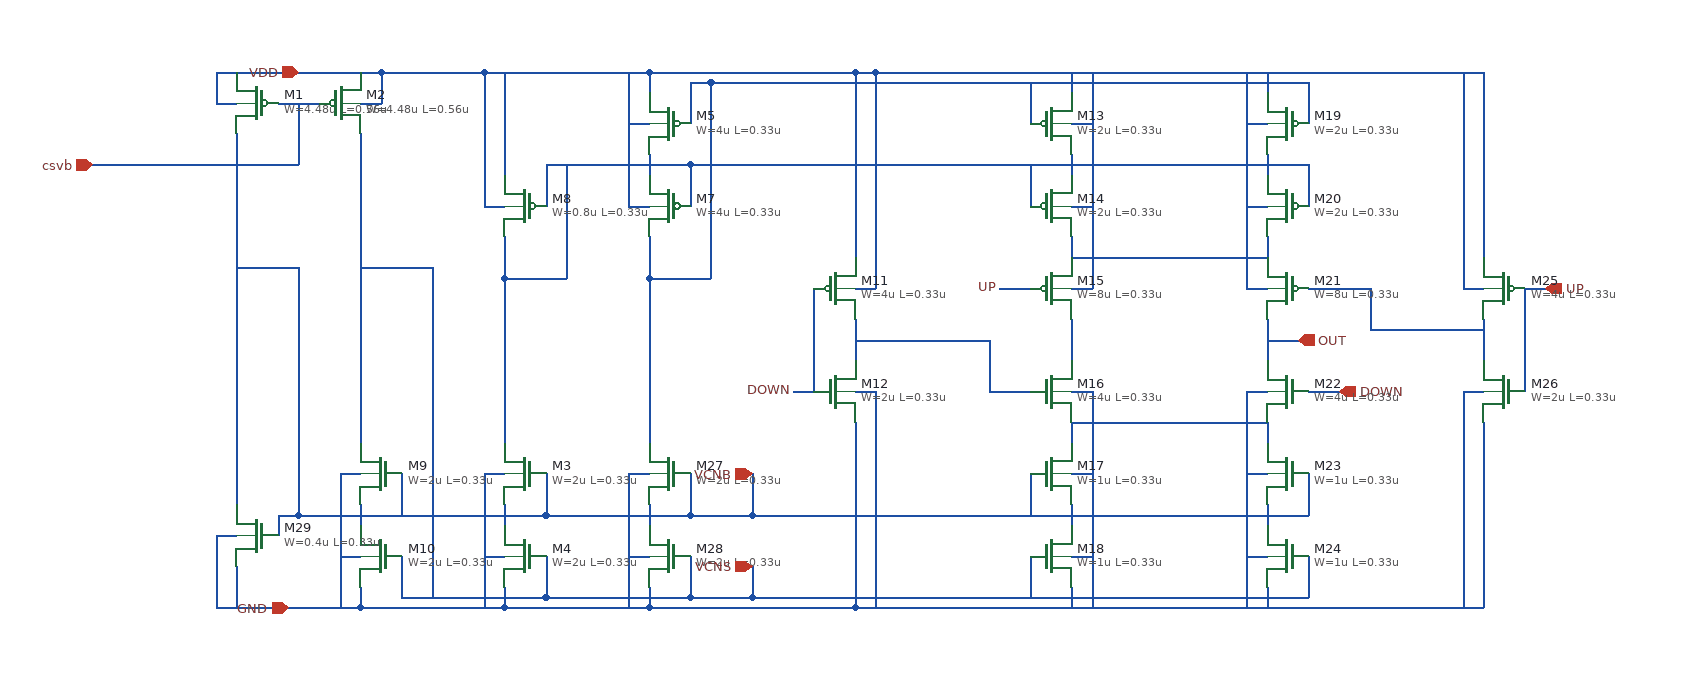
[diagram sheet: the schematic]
v {xschem version=3.4.5 file_version=1.2
}
G {}
K {}
V {}
S {}
E {}
N 900 -360 900 -320 {
lab=OUT}
N 940 -290 970 -290 {
lab=DOWN}
N 1110 -360 1110 -320 {
lab=#net1}
N 940 -390 980 -390 {
lab=#net1}
N 1150 -390 1150 -290 {
lab=UP}
N 1150 -390 1170 -390 {
lab=UP}
N 1090 -390 1110 -390 {
lab=VDD}
N 1090 -290 1110 -290 {
lab=GND}
N 880 -390 900 -390 {
lab=VDD}
N 880 -290 900 -290 {
lab=GND}
N 710 -360 710 -320 {
lab=#net2}
N 640 -390 670 -390 {
lab=UP}
N 500 -360 500 -320 {
lab=#net3}
N 630 -290 670 -290 {
lab=#net3}
N 630 -340 630 -290 {
lab=#net3}
N 500 -340 630 -340 {
lab=#net3}
N 460 -390 460 -290 {
lab=DOWN}
N 440 -290 460 -290 {
lab=DOWN}
N 500 -390 520 -390 {
lab=VDD}
N 500 -290 520 -290 {
lab=GND}
N 710 -390 730 -390 {
lab=VDD}
N 710 -290 730 -290 {
lab=GND}
N 710 -420 900 -420 {
lab=#net4}
N 710 -260 900 -260 {
lab=#net5}
N 900 -340 930 -340 {
lab=OUT}
N 980 -390 1000 -390 {
lab=#net1}
N 1000 -350 1110 -350 {
lab=#net1}
N 1000 -390 1000 -350 {
lab=#net1}
N 710 -210 730 -210 {
lab=GND}
N 710 -130 730 -130 {
lab=GND}
N 900 -600 900 -580 {
lab=VDD}
N 880 -550 900 -550 {
lab=VDD}
N 880 -470 900 -470 {
lab=VDD}
N 900 -520 900 -500 {
lab=#net6}
N 940 -510 940 -470 {
lab=#net7}
N 940 -590 940 -550 {
lab=#net8}
N 400 -590 760 -590 {
lab=#net8}
N 400 -510 760 -510 {
lab=#net7}
N 710 -180 710 -160 {
lab=#net9}
N 710 -100 710 -80 {
lab=GND}
N 670 -210 670 -170 {
lab=VCNB}
N 670 -130 670 -90 {
lab=GND}
N 900 -440 900 -420 {
lab=#net4}
N 500 -600 500 -420 {
lab=VDD}
N 520 -600 520 -390 {
lab=VDD}
N 730 -600 730 -390 {
lab=VDD}
N 880 -600 880 -390 {
lab=VDD}
N 1110 -600 1110 -420 {
lab=VDD}
N 1090 -600 1090 -390 {
lab=VDD}
N 500 -260 500 -80 {
lab=GND}
N 520 -290 520 -80 {
lab=GND}
N 880 -290 880 -80 {
lab=GND}
N 710 -260 710 -240 {
lab=#net5}
N 1090 -290 1090 -80 {
lab=GND}
N 1110 -260 1110 -80 {
lab=GND}
N 500 -80 1110 -80 {
lab=GND}
N 710 -600 710 -580 {
lab=VDD}
N 710 -550 730 -550 {
lab=VDD}
N 710 -470 730 -470 {
lab=VDD}
N 710 -520 710 -500 {
lab=#net10}
N 670 -510 670 -470 {
lab=#net7}
N 670 -590 670 -550 {
lab=#net8}
N 710 -440 710 -420 {
lab=#net4}
N 730 -290 730 -80 {
lab=GND}
N 880 -210 900 -210 {
lab=GND}
N 880 -130 900 -130 {
lab=GND}
N 900 -180 900 -160 {
lab=#net11}
N 900 -100 900 -80 {
lab=GND}
N 940 -210 940 -170 {
lab=VCNB}
N 940 -130 940 -90 {
lab=GND}
N 900 -260 900 -240 {
lab=#net5}
N 760 -90 940 -90 {
lab=GND}
N 760 -170 940 -170 {
lab=VCNB}
N 760 -590 940 -590 {
lab=#net8}
N 760 -510 940 -510 {
lab=#net7}
N 520 -600 1110 -600 {
lab=VDD}
N 500 -600 520 -600 {
lab=VDD}
N 400 -170 760 -170 {
lab=VCNB}
N 400 -90 760 -90 {
lab=GND}
N -120 -570 -100 -570 {
lab=VDD}
N -120 -600 -120 -570 {
lab=VDD}
N -60 -570 -20 -570 {
lab=csvb}
N -120 -600 -100 -600 {
lab=VDD}
N 20 -570 40 -570 {
lab=VDD}
N 40 -600 40 -570 {
lab=VDD}
N 20 -600 40 -600 {
lab=VDD}
N -100 -600 20 -600 {
lab=VDD}
N 0 -210 20 -210 {
lab=GND}
N 0 -210 0 -80 {
lab=GND}
N 0 -130 20 -130 {
lab=GND}
N 20 -180 20 -160 {
lab=#net12}
N 20 -100 20 -80 {
lab=GND}
N -120 -80 -20 -80 {
lab=GND}
N -60 -170 -40 -170 {
lab=VCNB}
N -100 -410 -40 -410 {
lab=VCNB}
N 60 -210 60 -170 {
lab=VCNB}
N 60 -130 60 -90 {
lab=GND}
N 60 -90 80 -90 {
lab=GND}
N -40 -170 100 -170 {
lab=VCNB}
N -40 -280 -40 -170 {
lab=VCNB}
N -100 -450 -100 -370 {
lab=VCNB}
N -20 -80 20 -80 {
lab=GND}
N 20 -450 20 -370 {
lab=GND}
N 140 -210 160 -210 {
lab=GND}
N 140 -130 160 -130 {
lab=GND}
N 160 -180 160 -160 {
lab=#net13}
N 160 -100 160 -80 {
lab=GND}
N 200 -210 200 -170 {
lab=VCNB}
N 200 -130 200 -90 {
lab=GND}
N 100 -170 200 -170 {
lab=VCNB}
N 80 -90 200 -90 {
lab=GND}
N 20 -80 160 -80 {
lab=GND}
N 140 -210 140 -80 {
lab=GND}
N 300 -600 300 -580 {
lab=VDD}
N 280 -550 300 -550 {
lab=VDD}
N 280 -470 300 -470 {
lab=VDD}
N 280 -600 280 -470 {
lab=VDD}
N 300 -520 300 -500 {
lab=#net14}
N 340 -510 340 -470 {
lab=#net7}
N 340 -590 340 -550 {
lab=#net8}
N 300 -400 360 -400 {
lab=#net8}
N 160 -600 160 -500 {
lab=VDD}
N 140 -470 160 -470 {
lab=VDD}
N 140 -600 140 -470 {
lab=VDD}
N 200 -510 340 -510 {
lab=#net7}
N 200 -510 200 -470 {
lab=#net7}
N 160 -400 220 -400 {
lab=#net7}
N 140 -600 240 -600 {
lab=VDD}
N 160 -440 160 -400 {
lab=#net7}
N 300 -440 300 -400 {
lab=#net8}
N 220 -510 220 -400 {
lab=#net7}
N 340 -590 360 -590 {
lab=#net8}
N 360 -590 360 -400 {
lab=#net8}
N 240 -600 300 -600 {
lab=VDD}
N 160 -400 160 -370 {
lab=#net7}
N 280 -210 300 -210 {
lab=GND}
N 280 -130 300 -130 {
lab=GND}
N 300 -180 300 -160 {
lab=#net15}
N 300 -100 300 -80 {
lab=GND}
N 340 -210 340 -170 {
lab=VCNB}
N 340 -130 340 -90 {
lab=GND}
N 240 -170 340 -170 {
lab=VCNB}
N 280 -210 280 -80 {
lab=GND}
N 160 -80 300 -80 {
lab=GND}
N 200 -170 240 -170 {
lab=VCNB}
N 200 -90 340 -90 {
lab=GND}
N 300 -400 300 -370 {
lab=#net8}
N 340 -510 400 -510 {
lab=#net7}
N 360 -590 400 -590 {
lab=#net8}
N 20 -540 20 -450 {
lab=GND}
N -100 -540 -100 -450 {
lab=VCNB}
N -240 -510 -40 -510 {
lab=csvb}
N 40 -600 140 -600 {
lab=VDD}
N 90 -270 90 -90 {
lab=GND}
N 20 -410 90 -410 {
lab=GND}
N 90 -410 90 -400 {
lab=GND}
N -40 -570 -40 -510 {
lab=csvb}
N -120 -150 -100 -150 {
lab=GND}
N -100 -120 -100 -80 {
lab=GND}
N -60 -170 -60 -150 {
lab=VCNB}
N 340 -90 400 -90 {
lab=GND}
N 340 -170 400 -170 {
lab=VCNB}
N 310 -80 500 -80 {
lab=GND}
N 300 -80 310 -80 {
lab=GND}
N 300 -600 500 -600 {
lab=VDD}
N 300 -370 300 -240 {
lab=#net8}
N 160 -370 160 -240 {
lab=#net7}
N 90 -400 90 -270 {
lab=GND}
N 20 -370 20 -240 {
lab=GND}
N -100 -370 -100 -240 {
lab=VCNB}
N -40 -410 -40 -280 {
lab=VCNB}
N 400 -120 400 -90 {
lab=GND}
N 400 -210 400 -170 {
lab=VCNB}
N -120 -150 -120 -80 {
lab=GND}
N -100 -240 -100 -180 {
lab=VCNB}
C {devices/ipin.sym} 970 -290 0 1 {name=p7 lab=DOWN}
C {devices/ipin.sym} 1170 -390 0 1 {name=p6 lab=UP}
C {symbols/pfet_03v3.sym} 690 -390 0 0 {name=M15
L=0.33u
W=8u
nf=1
mult=1
ad="'int((nf+1)/2) * W/nf * 0.18u'"
pd="'2*int((nf+1)/2) * (W/nf + 0.18u)'"
as="'int((nf+2)/2) * W/nf * 0.18u'"
ps="'2*int((nf+2)/2) * (W/nf + 0.18u)'"
nrd="'0.18u / W'" nrs="'0.18u / W'"
sa=0 sb=0 sd=0
model=pfet_03v3
spiceprefix=X
}
C {symbols/nfet_03v3.sym} 690 -290 0 0 {name=M16
L=0.33u
W=4u
nf=1
mult=1
ad="'int((nf+1)/2) * W/nf * 0.18u'"
pd="'2*int((nf+1)/2) * (W/nf + 0.18u)'"
as="'int((nf+2)/2) * W/nf * 0.18u'"
ps="'2*int((nf+2)/2) * (W/nf + 0.18u)'"
nrd="'0.18u / W'" nrs="'0.18u / W'"
sa=0 sb=0 sd=0
model=nfet_03v3
spiceprefix=X
}
C {symbols/pfet_03v3.sym} 480 -390 0 0 {name=M11
L=0.33u
W=4u
nf=1
mult=1
ad="'int((nf+1)/2) * W/nf * 0.18u'"
pd="'2*int((nf+1)/2) * (W/nf + 0.18u)'"
as="'int((nf+2)/2) * W/nf * 0.18u'"
ps="'2*int((nf+2)/2) * (W/nf + 0.18u)'"
nrd="'0.18u / W'" nrs="'0.18u / W'"
sa=0 sb=0 sd=0
model=pfet_03v3
spiceprefix=X
}
C {symbols/nfet_03v3.sym} 480 -290 0 0 {name=M12
L=0.33u
W=2u
nf=1
mult=1
ad="'int((nf+1)/2) * W/nf * 0.18u'"
pd="'2*int((nf+1)/2) * (W/nf + 0.18u)'"
as="'int((nf+2)/2) * W/nf * 0.18u'"
ps="'2*int((nf+2)/2) * (W/nf + 0.18u)'"
nrd="'0.18u / W'" nrs="'0.18u / W'"
sa=0 sb=0 sd=0
model=nfet_03v3
spiceprefix=X
}
C {devices/lab_wire.sym} 440 -290 0 0 {name=p3 sig_type=std_logic lab=DOWN}
C {devices/lab_wire.sym} 640 -390 0 0 {name=p4 sig_type=std_logic lab=UP}
C {symbols/nfet_03v3.sym} 690 -210 0 0 {name=M17
L=0.33u
W=1u
nf=1
mult=1
ad="'int((nf+1)/2) * W/nf * 0.18u'"
pd="'2*int((nf+1)/2) * (W/nf + 0.18u)'"
as="'int((nf+2)/2) * W/nf * 0.18u'"
ps="'2*int((nf+2)/2) * (W/nf + 0.18u)'"
nrd="'0.18u / W'" nrs="'0.18u / W'"
sa=0 sb=0 sd=0
model=nfet_03v3
spiceprefix=X
}
C {devices/opin.sym} 930 -340 0 0 {name=p5 lab=OUT}
C {symbols/nfet_03v3.sym} 690 -130 0 0 {name=M18
L=0.33u
W=1u
nf=1
mult=1
ad="'int((nf+1)/2) * W/nf * 0.18u'"
pd="'2*int((nf+1)/2) * (W/nf + 0.18u)'"
as="'int((nf+2)/2) * W/nf * 0.18u'"
ps="'2*int((nf+2)/2) * (W/nf + 0.18u)'"
nrd="'0.18u / W'" nrs="'0.18u / W'"
sa=0 sb=0 sd=0
model=nfet_03v3
spiceprefix=X
}
C {symbols/pfet_03v3.sym} 690 -550 0 0 {name=M13
L=0.33u
W=2u
nf=1
mult=1
ad="'int((nf+1)/2) * W/nf * 0.18u'"
pd="'2*int((nf+1)/2) * (W/nf + 0.18u)'"
as="'int((nf+2)/2) * W/nf * 0.18u'"
ps="'2*int((nf+2)/2) * (W/nf + 0.18u)'"
nrd="'0.18u / W'" nrs="'0.18u / W'"
sa=0 sb=0 sd=0
model=pfet_03v3
spiceprefix=X
}
C {symbols/pfet_03v3.sym} 690 -470 0 0 {name=M14
L=0.33u
W=2u
nf=1
mult=1
ad="'int((nf+1)/2) * W/nf * 0.18u'"
pd="'2*int((nf+1)/2) * (W/nf + 0.18u)'"
as="'int((nf+2)/2) * W/nf * 0.18u'"
ps="'2*int((nf+2)/2) * (W/nf + 0.18u)'"
nrd="'0.18u / W'" nrs="'0.18u / W'"
sa=0 sb=0 sd=0
model=pfet_03v3
spiceprefix=X
}
C {symbols/pfet_03v3.sym} 920 -550 0 1 {name=M19
L=0.33u
W=2u
nf=1
mult=1
ad="'int((nf+1)/2) * W/nf * 0.18u'"
pd="'2*int((nf+1)/2) * (W/nf + 0.18u)'"
as="'int((nf+2)/2) * W/nf * 0.18u'"
ps="'2*int((nf+2)/2) * (W/nf + 0.18u)'"
nrd="'0.18u / W'" nrs="'0.18u / W'"
sa=0 sb=0 sd=0
model=pfet_03v3
spiceprefix=X
}
C {symbols/pfet_03v3.sym} 920 -470 0 1 {name=M20
L=0.33u
W=2u
nf=1
mult=1
ad="'int((nf+1)/2) * W/nf * 0.18u'"
pd="'2*int((nf+1)/2) * (W/nf + 0.18u)'"
as="'int((nf+2)/2) * W/nf * 0.18u'"
ps="'2*int((nf+2)/2) * (W/nf + 0.18u)'"
nrd="'0.18u / W'" nrs="'0.18u / W'"
sa=0 sb=0 sd=0
model=pfet_03v3
spiceprefix=X
}
C {symbols/pfet_03v3.sym} 920 -390 0 1 {name=M21
L=0.33u
W=8u
nf=1
mult=1
ad="'int((nf+1)/2) * W/nf * 0.18u'"
pd="'2*int((nf+1)/2) * (W/nf + 0.18u)'"
as="'int((nf+2)/2) * W/nf * 0.18u'"
ps="'2*int((nf+2)/2) * (W/nf + 0.18u)'"
nrd="'0.18u / W'" nrs="'0.18u / W'"
sa=0 sb=0 sd=0
model=pfet_03v3
spiceprefix=X
}
C {symbols/nfet_03v3.sym} 920 -290 0 1 {name=M22
L=0.33u
W=4u
nf=1
mult=1
ad="'int((nf+1)/2) * W/nf * 0.18u'"
pd="'2*int((nf+1)/2) * (W/nf + 0.18u)'"
as="'int((nf+2)/2) * W/nf * 0.18u'"
ps="'2*int((nf+2)/2) * (W/nf + 0.18u)'"
nrd="'0.18u / W'" nrs="'0.18u / W'"
sa=0 sb=0 sd=0
model=nfet_03v3
spiceprefix=X
}
C {symbols/nfet_03v3.sym} 920 -210 0 1 {name=M23
L=0.33u
W=1u
nf=1
mult=1
ad="'int((nf+1)/2) * W/nf * 0.18u'"
pd="'2*int((nf+1)/2) * (W/nf + 0.18u)'"
as="'int((nf+2)/2) * W/nf * 0.18u'"
ps="'2*int((nf+2)/2) * (W/nf + 0.18u)'"
nrd="'0.18u / W'" nrs="'0.18u / W'"
sa=0 sb=0 sd=0
model=nfet_03v3
spiceprefix=X
}
C {symbols/nfet_03v3.sym} 920 -130 0 1 {name=M24
L=0.33u
W=1u
nf=1
mult=1
ad="'int((nf+1)/2) * W/nf * 0.18u'"
pd="'2*int((nf+1)/2) * (W/nf + 0.18u)'"
as="'int((nf+2)/2) * W/nf * 0.18u'"
ps="'2*int((nf+2)/2) * (W/nf + 0.18u)'"
nrd="'0.18u / W'" nrs="'0.18u / W'"
sa=0 sb=0 sd=0
model=nfet_03v3
spiceprefix=X
}
C {symbols/pfet_03v3.sym} 1130 -390 0 1 {name=M25
L=0.33u
W=4u
nf=1
mult=1
ad="'int((nf+1)/2) * W/nf * 0.18u'"
pd="'2*int((nf+1)/2) * (W/nf + 0.18u)'"
as="'int((nf+2)/2) * W/nf * 0.18u'"
ps="'2*int((nf+2)/2) * (W/nf + 0.18u)'"
nrd="'0.18u / W'" nrs="'0.18u / W'"
sa=0 sb=0 sd=0
model=pfet_03v3
spiceprefix=X
}
C {symbols/nfet_03v3.sym} 1130 -290 0 1 {name=M26
L=0.33u
W=2u
nf=1
mult=1
ad="'int((nf+1)/2) * W/nf * 0.18u'"
pd="'2*int((nf+1)/2) * (W/nf + 0.18u)'"
as="'int((nf+2)/2) * W/nf * 0.18u'"
ps="'2*int((nf+2)/2) * (W/nf + 0.18u)'"
nrd="'0.18u / W'" nrs="'0.18u / W'"
sa=0 sb=0 sd=0
model=nfet_03v3
spiceprefix=X
}
C {symbols/pfet_03v3.sym} -80 -570 0 1 {name=M1
L=0.56u
W=4.48u
nf=1
m=1
ad="'int((nf+1)/2) * W/nf * 0.18u'"
pd="'2*int((nf+1)/2) * (W/nf + 0.18u)'"
as="'int((nf+2)/2) * W/nf * 0.18u'"
ps="'2*int((nf+2)/2) * (W/nf + 0.18u)'"
nrd="'0.18u / W'" nrs="'0.18u / W'"
sa=0 sb=0 sd=0
model=pfet_03v3
spiceprefix=X
}
C {symbols/pfet_03v3.sym} 0 -570 0 0 {name=M2
L=0.56u
W=4.48u
nf=1
m=1
ad="'int((nf+1)/2) * W/nf * 0.18u'"
pd="'2*int((nf+1)/2) * (W/nf + 0.18u)'"
as="'int((nf+2)/2) * W/nf * 0.18u'"
ps="'2*int((nf+2)/2) * (W/nf + 0.18u)'"
nrd="'0.18u / W'" nrs="'0.18u / W'"
sa=0 sb=0 sd=0
model=pfet_03v3
spiceprefix=X
}
C {symbols/nfet_03v3.sym} 40 -210 0 1 {name=M9
L=0.33u
W=2u
nf=1
mult=1
ad="'int((nf+1)/2) * W/nf * 0.18u'"
pd="'2*int((nf+1)/2) * (W/nf + 0.18u)'"
as="'int((nf+2)/2) * W/nf * 0.18u'"
ps="'2*int((nf+2)/2) * (W/nf + 0.18u)'"
nrd="'0.18u / W'" nrs="'0.18u / W'"
sa=0 sb=0 sd=0
model=nfet_03v3
spiceprefix=X
}
C {symbols/nfet_03v3.sym} 40 -130 0 1 {name=M10
L=0.33u
W=2u
nf=1
mult=1
ad="'int((nf+1)/2) * W/nf * 0.18u'"
pd="'2*int((nf+1)/2) * (W/nf + 0.18u)'"
as="'int((nf+2)/2) * W/nf * 0.18u'"
ps="'2*int((nf+2)/2) * (W/nf + 0.18u)'"
nrd="'0.18u / W'" nrs="'0.18u / W'"
sa=0 sb=0 sd=0
model=nfet_03v3
spiceprefix=X
}
C {symbols/nfet_03v3.sym} 180 -210 0 1 {name=M3
L=0.33u
W=2u
nf=1
mult=1
ad="'int((nf+1)/2) * W/nf * 0.18u'"
pd="'2*int((nf+1)/2) * (W/nf + 0.18u)'"
as="'int((nf+2)/2) * W/nf * 0.18u'"
ps="'2*int((nf+2)/2) * (W/nf + 0.18u)'"
nrd="'0.18u / W'" nrs="'0.18u / W'"
sa=0 sb=0 sd=0
model=nfet_03v3
spiceprefix=X
}
C {symbols/nfet_03v3.sym} 180 -130 0 1 {name=M4
L=0.33u
W=2u
nf=1
mult=1
ad="'int((nf+1)/2) * W/nf * 0.18u'"
pd="'2*int((nf+1)/2) * (W/nf + 0.18u)'"
as="'int((nf+2)/2) * W/nf * 0.18u'"
ps="'2*int((nf+2)/2) * (W/nf + 0.18u)'"
nrd="'0.18u / W'" nrs="'0.18u / W'"
sa=0 sb=0 sd=0
model=nfet_03v3
spiceprefix=X
}
C {symbols/pfet_03v3.sym} 320 -550 0 1 {name=M5
L=0.33u
W=4u
nf=1
mult=1
ad="'int((nf+1)/2) * W/nf * 0.18u'"
pd="'2*int((nf+1)/2) * (W/nf + 0.18u)'"
as="'int((nf+2)/2) * W/nf * 0.18u'"
ps="'2*int((nf+2)/2) * (W/nf + 0.18u)'"
nrd="'0.18u / W'" nrs="'0.18u / W'"
sa=0 sb=0 sd=0
model=pfet_03v3
spiceprefix=X
}
C {symbols/pfet_03v3.sym} 320 -470 0 1 {name=M7
L=0.33u
W=4u
nf=1
mult=1
ad="'int((nf+1)/2) * W/nf * 0.18u'"
pd="'2*int((nf+1)/2) * (W/nf + 0.18u)'"
as="'int((nf+2)/2) * W/nf * 0.18u'"
ps="'2*int((nf+2)/2) * (W/nf + 0.18u)'"
nrd="'0.18u / W'" nrs="'0.18u / W'"
sa=0 sb=0 sd=0
model=pfet_03v3
spiceprefix=X
}
C {symbols/pfet_03v3.sym} 180 -470 0 1 {name=M8
L=0.33u
W=0.8u
nf=1
mult=1
ad="'int((nf+1)/2) * W/nf * 0.18u'"
pd="'2*int((nf+1)/2) * (W/nf + 0.18u)'"
as="'int((nf+2)/2) * W/nf * 0.18u'"
ps="'2*int((nf+2)/2) * (W/nf + 0.18u)'"
nrd="'0.18u / W'" nrs="'0.18u / W'"
sa=0 sb=0 sd=0
model=pfet_03v3
spiceprefix=X
}
C {symbols/nfet_03v3.sym} 320 -210 0 1 {name=M27
L=0.33u
W=2u
nf=1
mult=1
ad="'int((nf+1)/2) * W/nf * 0.18u'"
pd="'2*int((nf+1)/2) * (W/nf + 0.18u)'"
as="'int((nf+2)/2) * W/nf * 0.18u'"
ps="'2*int((nf+2)/2) * (W/nf + 0.18u)'"
nrd="'0.18u / W'" nrs="'0.18u / W'"
sa=0 sb=0 sd=0
model=nfet_03v3
spiceprefix=X
}
C {symbols/nfet_03v3.sym} 320 -130 0 1 {name=M28
L=0.33u
W=2u
nf=1
mult=1
ad="'int((nf+1)/2) * W/nf * 0.18u'"
pd="'2*int((nf+1)/2) * (W/nf + 0.18u)'"
as="'int((nf+2)/2) * W/nf * 0.18u'"
ps="'2*int((nf+2)/2) * (W/nf + 0.18u)'"
nrd="'0.18u / W'" nrs="'0.18u / W'"
sa=0 sb=0 sd=0
model=nfet_03v3
spiceprefix=X
}
C {devices/ipin.sym} -240 -510 0 0 {name=p14 lab=csvb}
C {symbols/nfet_03v3.sym} -80 -150 0 1 {name=M29
L=0.33u
W=0.4u
nf=1
mult=1
ad="'int((nf+1)/2) * W/nf * 0.18u'"
pd="'2*int((nf+1)/2) * (W/nf + 0.18u)'"
as="'int((nf+2)/2) * W/nf * 0.18u'"
ps="'2*int((nf+2)/2) * (W/nf + 0.18u)'"
nrd="'0.18u / W'" nrs="'0.18u / W'"
sa=0 sb=0 sd=0
model=nfet_03v3
spiceprefix=X
}
C {devices/iopin.sym} -40 -600 3 0 {name=p1 lab=VDD}
C {devices/iopin.sym} -50 -80 1 0 {name=p2 lab=GND}
C {devices/iopin.sym} 400 -120 0 0 {name=p8 lab=VCNS}
C {devices/iopin.sym} 400 -210 0 0 {name=p9 lab=VCNB}
